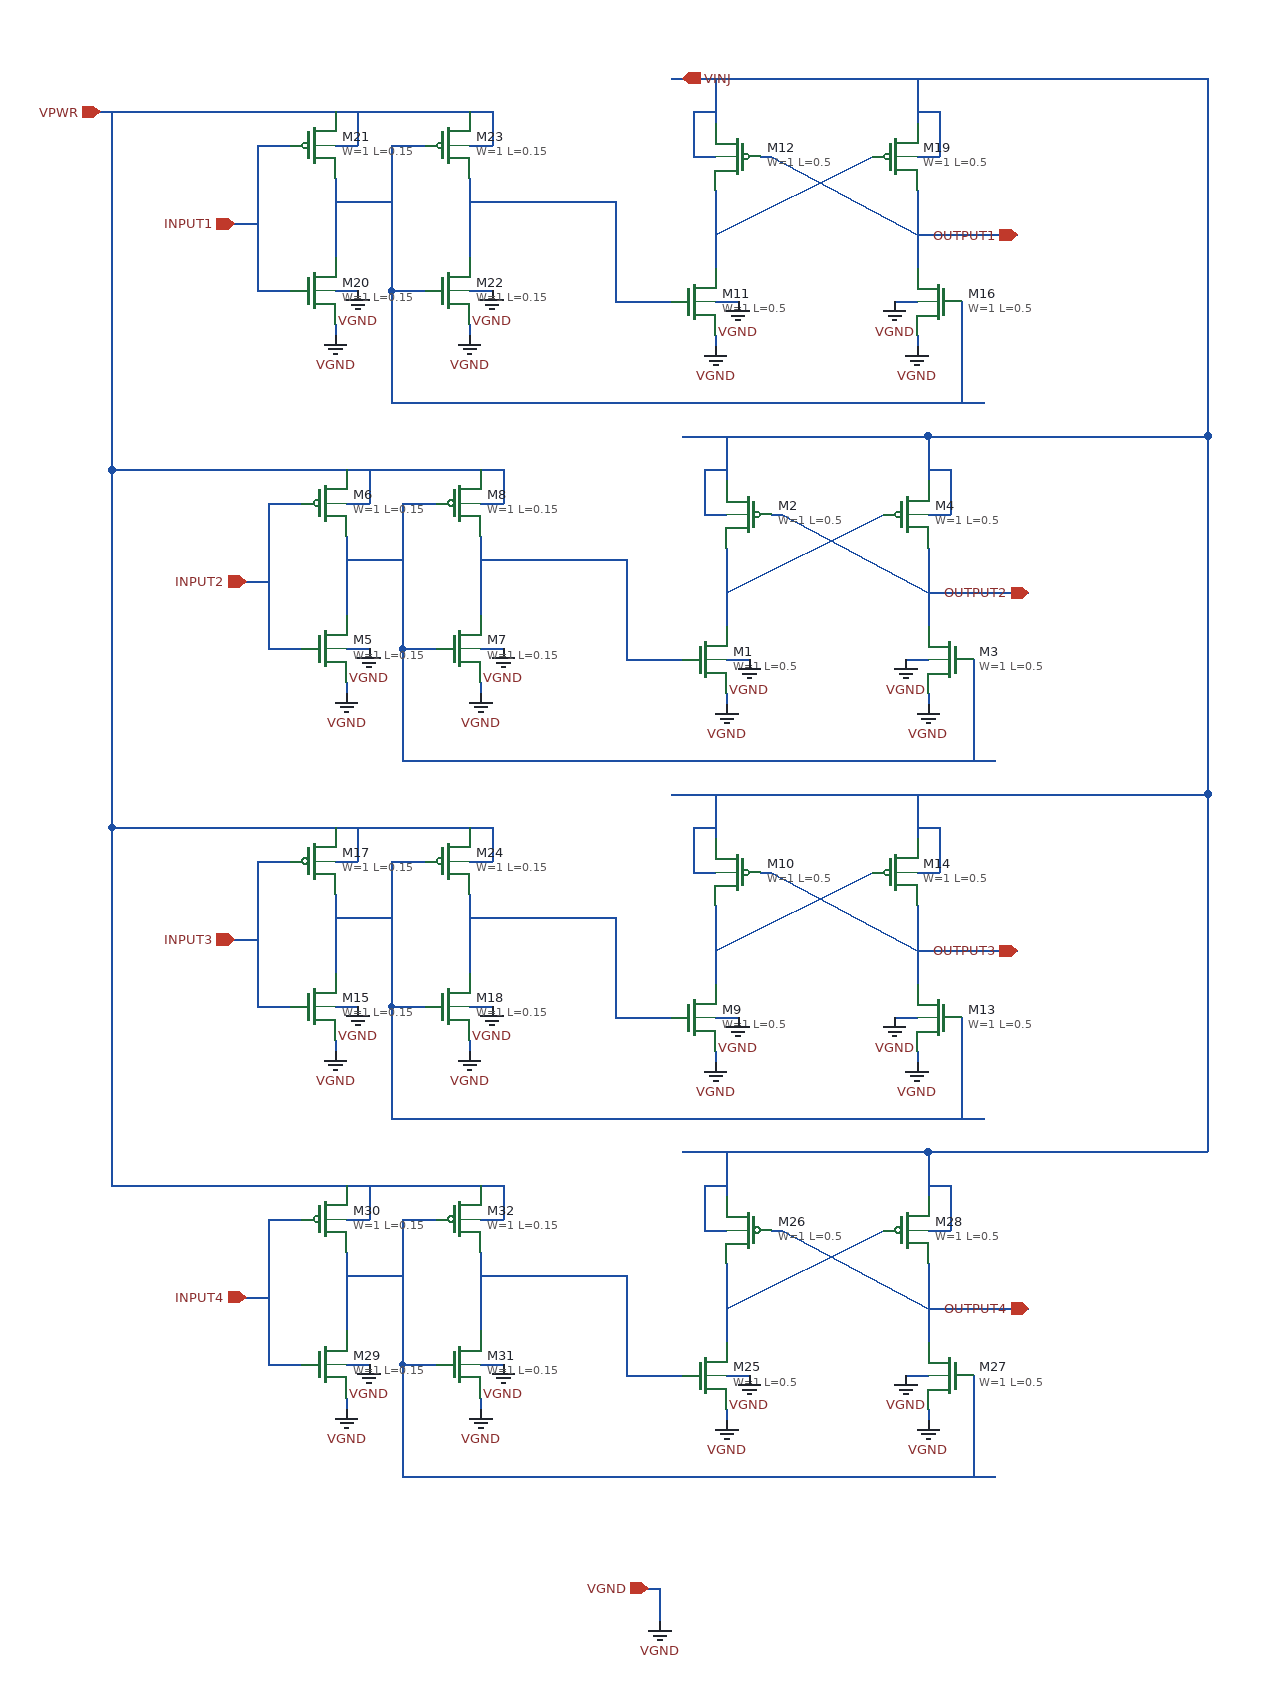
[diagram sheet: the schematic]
v {xschem version=2.9.9 file_version=1.2 }
G {}
K {}
V {}
S {}
E {}
N 2380 -1040 2380 -990 { lab=#net1}
N 2090 -1040 2120 -1040 { lab=#net2}
N 2320 -1040 2340 -1040 { lab=VGND}
N 2160 -1010 2160 -1000 { lab=VGND}
N 2160 -1040 2180 -1040 { lab=VGND}
N 1820 -1150 1820 -1080 { lab=#net1}
N 1750 -1050 1780 -1050 { lab=INPUT1}
N 1750 -1180 1780 -1180 { lab=INPUT1}
N 1820 -1180 1840 -1180 { lab=VPWR}
N 1840 -1210 1840 -1180 { lab=VPWR}
N 1820 -1210 1840 -1210 { lab=VPWR}
N 1650 -1210 1820 -1210 { lab=VPWR}
N 1820 -1020 1820 -1010 { lab=VGND}
N 1820 -1050 1840 -1050 { lab=VGND}
N 1820 -1130 1870 -1130 { lab=#net1}
N 1750 -1180 1750 -1050 { lab=INPUT1}
N 1730 -1110 1750 -1110 { lab=INPUT1}
N 1940 -1150 1940 -1080 { lab=#net2}
N 1870 -1050 1900 -1050 { lab=#net1}
N 1870 -1180 1900 -1180 { lab=#net1}
N 1940 -1180 1960 -1180 { lab=VPWR}
N 1960 -1210 1960 -1180 { lab=VPWR}
N 1940 -1210 1960 -1210 { lab=VPWR}
N 1940 -1020 1940 -1010 { lab=VGND}
N 1940 -1050 1960 -1050 { lab=VGND}
N 1940 -1130 1990 -1130 { lab=#net2}
N 1870 -1180 1870 -1050 { lab=#net1}
N 1830 -1210 1940 -1210 { lab=VPWR}
N 1870 -1050 1870 -950 { lab=#net1}
N 1870 -950 2000 -950 { lab=#net1}
N 2340 -1010 2340 -1000 { lab=VGND}
N 2120 -1240 2340 -1240 { lab=VINJ}
N 2160 -1240 2160 -1200 { lab=VINJ}
N 2340 -1240 2340 -1200 { lab=VINJ}
N 2140 -1210 2140 -1170 { lab=VINJ}
N 2140 -1170 2160 -1170 { lab=VINJ}
N 2340 -1170 2360 -1170 { lab=VINJ}
N 2360 -1210 2360 -1170 { lab=VINJ}
N 2340 -1210 2360 -1210 { lab=VINJ}
N 2160 -1140 2160 -1070 { lab=#net3}
N 2340 -1140 2340 -1070 { lab=OUTPUT1}
N 2210 -1170 2340 -1100 { lab=OUTPUT1}
N 2160 -1100 2300 -1170 { lab=#net3}
N 2340 -1100 2430 -1100 { lab=OUTPUT1}
N 2000 -950 2400 -950 { lab=#net1}
N 1990 -1130 2070 -1130 { lab=#net2}
N 2070 -1130 2070 -1040 { lab=#net2}
N 2070 -1040 2090 -1040 { lab=#net2}
N 2330 -1240 2600 -1240 { lab=VINJ}
N 1610 -1210 1650 -1210 { lab=VPWR}
N 2390 -720 2390 -670 { lab=#net4}
N 2100 -720 2130 -720 { lab=#net5}
N 2330 -720 2350 -720 { lab=VGND}
N 2170 -690 2170 -680 { lab=VGND}
N 2170 -720 2190 -720 { lab=VGND}
N 1830 -830 1830 -760 { lab=#net4}
N 1760 -730 1790 -730 { lab=INPUT2}
N 1760 -860 1790 -860 { lab=INPUT2}
N 1830 -860 1850 -860 { lab=VPWR}
N 1850 -890 1850 -860 { lab=VPWR}
N 1830 -890 1850 -890 { lab=VPWR}
N 1660 -890 1830 -890 { lab=VPWR}
N 1830 -700 1830 -690 { lab=VGND}
N 1830 -730 1850 -730 { lab=VGND}
N 1830 -810 1880 -810 { lab=#net4}
N 1760 -860 1760 -730 { lab=INPUT2}
N 1740 -790 1760 -790 { lab=INPUT2}
N 1950 -830 1950 -760 { lab=#net5}
N 1880 -730 1910 -730 { lab=#net4}
N 1880 -860 1910 -860 { lab=#net4}
N 1950 -860 1970 -860 { lab=VPWR}
N 1970 -890 1970 -860 { lab=VPWR}
N 1950 -890 1970 -890 { lab=VPWR}
N 1950 -700 1950 -690 { lab=VGND}
N 1950 -730 1970 -730 { lab=VGND}
N 1950 -810 2000 -810 { lab=#net5}
N 1880 -860 1880 -730 { lab=#net4}
N 1840 -890 1950 -890 { lab=VPWR}
N 1880 -730 1880 -630 { lab=#net4}
N 1880 -630 2010 -630 { lab=#net4}
N 2350 -690 2350 -680 { lab=VGND}
N 2130 -920 2350 -920 { lab=VINJ}
N 2170 -920 2170 -880 { lab=VINJ}
N 2350 -920 2350 -880 { lab=VINJ}
N 2150 -890 2170 -890 { lab=VINJ}
N 2150 -890 2150 -850 { lab=VINJ}
N 2150 -850 2170 -850 { lab=VINJ}
N 2350 -850 2370 -850 { lab=VINJ}
N 2370 -890 2370 -850 { lab=VINJ}
N 2350 -890 2370 -890 { lab=VINJ}
N 2170 -820 2170 -750 { lab=#net6}
N 2350 -820 2350 -750 { lab=OUTPUT2}
N 2220 -850 2350 -780 { lab=OUTPUT2}
N 2170 -780 2310 -850 { lab=#net6}
N 2350 -780 2440 -780 { lab=OUTPUT2}
N 2010 -630 2410 -630 { lab=#net4}
N 2000 -810 2080 -810 { lab=#net5}
N 2080 -810 2080 -720 { lab=#net5}
N 2080 -720 2100 -720 { lab=#net5}
N 1620 -890 1660 -890 { lab=VPWR}
N 1620 -1210 1620 -890 { lab=VPWR}
N 1620 -890 1620 -620 { lab=VPWR}
N 2600 -1240 2600 -920 { lab=VINJ}
N 2600 -920 2600 -620 { lab=VINJ}
N 2350 -920 2600 -920 { lab=VINJ}
N 2380 -400 2380 -350 { lab=#net7}
N 2090 -400 2120 -400 { lab=#net8}
N 2320 -400 2340 -400 { lab=VGND}
N 2160 -370 2160 -360 { lab=VGND}
N 2160 -400 2180 -400 { lab=VGND}
N 1820 -510 1820 -440 { lab=#net7}
N 1750 -410 1780 -410 { lab=INPUT3}
N 1750 -540 1780 -540 { lab=INPUT3}
N 1820 -540 1840 -540 { lab=VPWR}
N 1840 -570 1840 -540 { lab=VPWR}
N 1820 -570 1840 -570 { lab=VPWR}
N 1650 -570 1820 -570 { lab=VPWR}
N 1820 -380 1820 -370 { lab=VGND}
N 1820 -410 1840 -410 { lab=VGND}
N 1820 -490 1870 -490 { lab=#net7}
N 1750 -540 1750 -410 { lab=INPUT3}
N 1730 -470 1750 -470 { lab=INPUT3}
N 1940 -510 1940 -440 { lab=#net8}
N 1870 -410 1900 -410 { lab=#net7}
N 1870 -540 1900 -540 { lab=#net7}
N 1940 -540 1960 -540 { lab=VPWR}
N 1960 -570 1960 -540 { lab=VPWR}
N 1940 -570 1960 -570 { lab=VPWR}
N 1940 -380 1940 -370 { lab=VGND}
N 1940 -410 1960 -410 { lab=VGND}
N 1940 -490 1990 -490 { lab=#net8}
N 1870 -540 1870 -410 { lab=#net7}
N 1830 -570 1940 -570 { lab=VPWR}
N 1870 -410 1870 -310 { lab=#net7}
N 1870 -310 2000 -310 { lab=#net7}
N 2340 -370 2340 -360 { lab=VGND}
N 2120 -600 2340 -600 { lab=VINJ}
N 2160 -600 2160 -560 { lab=VINJ}
N 2340 -600 2340 -560 { lab=VINJ}
N 2140 -570 2160 -570 { lab=VINJ}
N 2140 -570 2140 -530 { lab=VINJ}
N 2140 -530 2160 -530 { lab=VINJ}
N 2340 -530 2360 -530 { lab=VINJ}
N 2360 -570 2360 -530 { lab=VINJ}
N 2340 -570 2360 -570 { lab=VINJ}
N 2160 -500 2160 -430 { lab=#net9}
N 2340 -500 2340 -430 { lab=OUTPUT3}
N 2210 -530 2340 -460 { lab=OUTPUT3}
N 2160 -460 2300 -530 { lab=#net9}
N 2340 -460 2430 -460 { lab=OUTPUT3}
N 2000 -310 2400 -310 { lab=#net7}
N 1990 -490 2070 -490 { lab=#net8}
N 2070 -490 2070 -400 { lab=#net8}
N 2070 -400 2090 -400 { lab=#net8}
N 2330 -600 2600 -600 { lab=VINJ}
N 2390 -80 2390 -30 { lab=#net10}
N 2100 -80 2130 -80 { lab=#net11}
N 2330 -80 2350 -80 { lab=VGND}
N 2170 -50 2170 -40 { lab=VGND}
N 2170 -80 2190 -80 { lab=VGND}
N 1830 -190 1830 -120 { lab=#net10}
N 1760 -90 1790 -90 { lab=INPUT4}
N 1760 -220 1790 -220 { lab=INPUT4}
N 1830 -220 1850 -220 { lab=VPWR}
N 1850 -250 1850 -220 { lab=VPWR}
N 1830 -250 1850 -250 { lab=VPWR}
N 1660 -250 1830 -250 { lab=VPWR}
N 1830 -60 1830 -50 { lab=VGND}
N 1830 -90 1850 -90 { lab=VGND}
N 1830 -170 1880 -170 { lab=#net10}
N 1760 -220 1760 -90 { lab=INPUT4}
N 1740 -150 1760 -150 { lab=INPUT4}
N 1950 -190 1950 -120 { lab=#net11}
N 1880 -90 1910 -90 { lab=#net10}
N 1880 -220 1910 -220 { lab=#net10}
N 1950 -220 1970 -220 { lab=VPWR}
N 1970 -250 1970 -220 { lab=VPWR}
N 1950 -250 1970 -250 { lab=VPWR}
N 1950 -60 1950 -50 { lab=VGND}
N 1950 -90 1970 -90 { lab=VGND}
N 1950 -170 2000 -170 { lab=#net11}
N 1880 -220 1880 -90 { lab=#net10}
N 1840 -250 1950 -250 { lab=VPWR}
N 1880 -90 1880 10 { lab=#net10}
N 1880 10 2010 10 { lab=#net10}
N 2350 -50 2350 -40 { lab=VGND}
N 2130 -280 2350 -280 { lab=VINJ}
N 2170 -280 2170 -240 { lab=VINJ}
N 2350 -280 2350 -240 { lab=VINJ}
N 2150 -250 2170 -250 { lab=VINJ}
N 2150 -250 2150 -210 { lab=VINJ}
N 2150 -210 2170 -210 { lab=VINJ}
N 2350 -210 2370 -210 { lab=VINJ}
N 2370 -250 2370 -210 { lab=VINJ}
N 2350 -250 2370 -250 { lab=VINJ}
N 2170 -180 2170 -110 { lab=#net12}
N 2350 -180 2350 -110 { lab=OUTPUT4}
N 2220 -210 2350 -140 { lab=OUTPUT4}
N 2170 -140 2310 -210 { lab=#net12}
N 2350 -140 2440 -140 { lab=OUTPUT4}
N 2010 10 2410 10 { lab=#net10}
N 2000 -170 2080 -170 { lab=#net11}
N 2080 -170 2080 -80 { lab=#net11}
N 2080 -80 2100 -80 { lab=#net11}
N 1620 -250 1660 -250 { lab=VPWR}
N 1620 -570 1620 -250 { lab=VPWR}
N 2600 -600 2600 -280 { lab=VINJ}
N 2350 -280 2600 -280 { lab=VINJ}
N 2600 -630 2600 -610 { lab=VINJ}
N 2600 -620 2600 -600 { lab=VINJ}
N 1620 -620 1620 -570 { lab=VPWR}
N 1620 -570 1650 -570 { lab=VPWR}
N 2200 -1170 2210 -1170 { lab=OUTPUT1}
N 2210 -850 2220 -850 { lab=OUTPUT2}
N 2200 -530 2210 -530 { lab=OUTPUT3}
N 2210 -210 2220 -210 { lab=OUTPUT4}
N 2140 -1210 2160 -1210 { lab=VINJ}
N 2390 -30 2390 10 { lab=#net10}
N 2380 -350 2380 -310 { lab=#net7}
N 2390 -670 2390 -630 { lab=#net4}
N 2380 -990 2380 -950 { lab=#net1}
N 2090 110 2110 110 {}
N 2110 110 2110 140 {}
C {sky130_fd_pr/nfet_g5v0d10v5.sym} 2140 -1040 0 0 {name=M11
L=0.5
W=1
nf=1
mult=1
ad="'int((nf+1)/2) * W/nf * 0.29'" 
pd="'2*int((nf+1)/2) * (W/nf + 0.29)'"
as="'int((nf+2)/2) * W/nf * 0.29'" 
ps="'2*int((nf+2)/2) * (W/nf + 0.29)'"
nrd="'0.29 / W'" nrs="'0.29 / W'"
sa=0 sb=0 sd=0
model=nfet_g5v0d10v5
spiceprefix=X
}
C {sky130_fd_pr/pfet_g5v0d10v5.sym} 2180 -1170 0 1 {name=M12
L=0.5
W=1
nf=1
mult=1
ad="'int((nf+1)/2) * W/nf * 0.29'" 
pd="'2*int((nf+1)/2) * (W/nf + 0.29)'"
as="'int((nf+2)/2) * W/nf * 0.29'" 
ps="'2*int((nf+2)/2) * (W/nf + 0.29)'"
nrd="'0.29 / W'" nrs="'0.29 / W'"
sa=0 sb=0 sd=0
model=pfet_g5v0d10v5
spiceprefix=X
}
C {sky130_fd_pr/nfet_g5v0d10v5.sym} 2360 -1040 0 1 {name=M16
L=0.5
W=1
nf=1
mult=1
ad="'int((nf+1)/2) * W/nf * 0.29'" 
pd="'2*int((nf+1)/2) * (W/nf + 0.29)'"
as="'int((nf+2)/2) * W/nf * 0.29'" 
ps="'2*int((nf+2)/2) * (W/nf + 0.29)'"
nrd="'0.29 / W'" nrs="'0.29 / W'"
sa=0 sb=0 sd=0
model=nfet_g5v0d10v5
spiceprefix=X
}
C {devices/gnd.sym} 2320 -1040 0 0 {name=l10 lab=VGND}
C {devices/gnd.sym} 2180 -1040 0 0 {name=l11 lab=VGND}
C {devices/gnd.sym} 2160 -1000 0 0 {name=l12 lab=VGND}
C {devices/iopin.sym} 2430 -1100 0 0 {name=OUTPUT1 lab=OUTPUT1}
C {devices/ipin.sym} 1730 -1110 0 0 {name=INPUT1 lab=INPUT1}
C {sky130_fd_pr/pfet_g5v0d10v5.sym} 2320 -1170 0 0 {name=M19
L=0.5
W=1
nf=1
mult=1
ad="'int((nf+1)/2) * W/nf * 0.29'" 
pd="'2*int((nf+1)/2) * (W/nf + 0.29)'"
as="'int((nf+2)/2) * W/nf * 0.29'" 
ps="'2*int((nf+2)/2) * (W/nf + 0.29)'"
nrd="'0.29 / W'" nrs="'0.29 / W'"
sa=0 sb=0 sd=0
model=pfet_g5v0d10v5
spiceprefix=X
}
C {devices/gnd.sym} 1840 -1050 0 0 {name=l13 lab=VGND}
C {devices/gnd.sym} 1820 -1010 0 0 {name=l14 lab=VGND}
C {sky130_fd_pr/nfet_01v8.sym} 1800 -1050 0 0 {name=M20
L=0.15
W=1
nf=1 
mult=1
ad="'int((nf+1)/2) * W/nf * 0.29'" 
pd="'2*int((nf+1)/2) * (W/nf + 0.29)'"
as="'int((nf+2)/2) * W/nf * 0.29'" 
ps="'2*int((nf+2)/2) * (W/nf + 0.29)'"
nrd="'0.29 / W'" nrs="'0.29 / W'"
sa=0 sb=0 sd=0
model=nfet_01v8
spiceprefix=X
}
C {sky130_fd_pr/pfet_01v8.sym} 1800 -1180 0 0 {name=M21
L=0.15
W=1
nf=1
mult=1
ad="'int((nf+1)/2) * W/nf * 0.29'" 
pd="'2*int((nf+1)/2) * (W/nf + 0.29)'"
as="'int((nf+2)/2) * W/nf * 0.29'" 
ps="'2*int((nf+2)/2) * (W/nf + 0.29)'"
nrd="'0.29 / W'" nrs="'0.29 / W'"
sa=0 sb=0 sd=0
model=pfet_01v8
spiceprefix=X
}
C {devices/ipin.sym} 1610 -1210 0 0 {name=VPWR lab=VPWR}
C {devices/gnd.sym} 1960 -1050 0 0 {name=l15 lab=VGND}
C {devices/gnd.sym} 1940 -1010 0 0 {name=l16 lab=VGND}
C {sky130_fd_pr/nfet_01v8.sym} 1920 -1050 0 0 {name=M22
L=0.15
W=1
nf=1 
mult=1
ad="'int((nf+1)/2) * W/nf * 0.29'" 
pd="'2*int((nf+1)/2) * (W/nf + 0.29)'"
as="'int((nf+2)/2) * W/nf * 0.29'" 
ps="'2*int((nf+2)/2) * (W/nf + 0.29)'"
nrd="'0.29 / W'" nrs="'0.29 / W'"
sa=0 sb=0 sd=0
model=nfet_01v8
spiceprefix=X
}
C {sky130_fd_pr/pfet_01v8.sym} 1920 -1180 0 0 {name=M23
L=0.15
W=1
nf=1
mult=1
ad="'int((nf+1)/2) * W/nf * 0.29'" 
pd="'2*int((nf+1)/2) * (W/nf + 0.29)'"
as="'int((nf+2)/2) * W/nf * 0.29'" 
ps="'2*int((nf+2)/2) * (W/nf + 0.29)'"
nrd="'0.29 / W'" nrs="'0.29 / W'"
sa=0 sb=0 sd=0
model=pfet_01v8
spiceprefix=X
}
C {devices/gnd.sym} 2340 -1000 0 0 {name=l17 lab=VGND}
C {sky130_fd_pr/nfet_g5v0d10v5.sym} 2150 -720 0 0 {name=M1
L=0.5
W=1
nf=1
mult=1
ad="'int((nf+1)/2) * W/nf * 0.29'" 
pd="'2*int((nf+1)/2) * (W/nf + 0.29)'"
as="'int((nf+2)/2) * W/nf * 0.29'" 
ps="'2*int((nf+2)/2) * (W/nf + 0.29)'"
nrd="'0.29 / W'" nrs="'0.29 / W'"
sa=0 sb=0 sd=0
model=nfet_g5v0d10v5
spiceprefix=X
}
C {sky130_fd_pr/pfet_g5v0d10v5.sym} 2190 -850 0 1 {name=M2
L=0.5
W=1
nf=1
mult=1
ad="'int((nf+1)/2) * W/nf * 0.29'" 
pd="'2*int((nf+1)/2) * (W/nf + 0.29)'"
as="'int((nf+2)/2) * W/nf * 0.29'" 
ps="'2*int((nf+2)/2) * (W/nf + 0.29)'"
nrd="'0.29 / W'" nrs="'0.29 / W'"
sa=0 sb=0 sd=0
model=pfet_g5v0d10v5
spiceprefix=X
}
C {sky130_fd_pr/nfet_g5v0d10v5.sym} 2370 -720 0 1 {name=M3
L=0.5
W=1
nf=1
mult=1
ad="'int((nf+1)/2) * W/nf * 0.29'" 
pd="'2*int((nf+1)/2) * (W/nf + 0.29)'"
as="'int((nf+2)/2) * W/nf * 0.29'" 
ps="'2*int((nf+2)/2) * (W/nf + 0.29)'"
nrd="'0.29 / W'" nrs="'0.29 / W'"
sa=0 sb=0 sd=0
model=nfet_g5v0d10v5
spiceprefix=X
}
C {devices/gnd.sym} 2330 -720 0 0 {name=l1 lab=VGND}
C {devices/gnd.sym} 2190 -720 0 0 {name=l2 lab=VGND}
C {devices/gnd.sym} 2170 -680 0 0 {name=l3 lab=VGND}
C {devices/iopin.sym} 2440 -780 0 0 {name=OUTPUT2 lab=OUTPUT2}
C {devices/ipin.sym} 1740 -790 0 0 {name=INPUT2 lab=INPUT2}
C {sky130_fd_pr/pfet_g5v0d10v5.sym} 2330 -850 0 0 {name=M4
L=0.5
W=1
nf=1
mult=1
ad="'int((nf+1)/2) * W/nf * 0.29'" 
pd="'2*int((nf+1)/2) * (W/nf + 0.29)'"
as="'int((nf+2)/2) * W/nf * 0.29'" 
ps="'2*int((nf+2)/2) * (W/nf + 0.29)'"
nrd="'0.29 / W'" nrs="'0.29 / W'"
sa=0 sb=0 sd=0
model=pfet_g5v0d10v5
spiceprefix=X
}
C {devices/gnd.sym} 1850 -730 0 0 {name=l4 lab=VGND}
C {devices/gnd.sym} 1830 -690 0 0 {name=l5 lab=VGND}
C {sky130_fd_pr/nfet_01v8.sym} 1810 -730 0 0 {name=M5
L=0.15
W=1
nf=1 
mult=1
ad="'int((nf+1)/2) * W/nf * 0.29'" 
pd="'2*int((nf+1)/2) * (W/nf + 0.29)'"
as="'int((nf+2)/2) * W/nf * 0.29'" 
ps="'2*int((nf+2)/2) * (W/nf + 0.29)'"
nrd="'0.29 / W'" nrs="'0.29 / W'"
sa=0 sb=0 sd=0
model=nfet_01v8
spiceprefix=X
}
C {sky130_fd_pr/pfet_01v8.sym} 1810 -860 0 0 {name=M6
L=0.15
W=1
nf=1
mult=1
ad="'int((nf+1)/2) * W/nf * 0.29'" 
pd="'2*int((nf+1)/2) * (W/nf + 0.29)'"
as="'int((nf+2)/2) * W/nf * 0.29'" 
ps="'2*int((nf+2)/2) * (W/nf + 0.29)'"
nrd="'0.29 / W'" nrs="'0.29 / W'"
sa=0 sb=0 sd=0
model=pfet_01v8
spiceprefix=X
}
C {devices/gnd.sym} 1970 -730 0 0 {name=l6 lab=VGND}
C {devices/gnd.sym} 1950 -690 0 0 {name=l7 lab=VGND}
C {sky130_fd_pr/nfet_01v8.sym} 1930 -730 0 0 {name=M7
L=0.15
W=1
nf=1 
mult=1
ad="'int((nf+1)/2) * W/nf * 0.29'" 
pd="'2*int((nf+1)/2) * (W/nf + 0.29)'"
as="'int((nf+2)/2) * W/nf * 0.29'" 
ps="'2*int((nf+2)/2) * (W/nf + 0.29)'"
nrd="'0.29 / W'" nrs="'0.29 / W'"
sa=0 sb=0 sd=0
model=nfet_01v8
spiceprefix=X
}
C {sky130_fd_pr/pfet_01v8.sym} 1930 -860 0 0 {name=M8
L=0.15
W=1
nf=1
mult=1
ad="'int((nf+1)/2) * W/nf * 0.29'" 
pd="'2*int((nf+1)/2) * (W/nf + 0.29)'"
as="'int((nf+2)/2) * W/nf * 0.29'" 
ps="'2*int((nf+2)/2) * (W/nf + 0.29)'"
nrd="'0.29 / W'" nrs="'0.29 / W'"
sa=0 sb=0 sd=0
model=pfet_01v8
spiceprefix=X
}
C {devices/gnd.sym} 2350 -680 0 0 {name=l8 lab=VGND}
C {sky130_fd_pr/nfet_g5v0d10v5.sym} 2140 -400 0 0 {name=M9
L=0.5
W=1
nf=1
mult=1
ad="'int((nf+1)/2) * W/nf * 0.29'" 
pd="'2*int((nf+1)/2) * (W/nf + 0.29)'"
as="'int((nf+2)/2) * W/nf * 0.29'" 
ps="'2*int((nf+2)/2) * (W/nf + 0.29)'"
nrd="'0.29 / W'" nrs="'0.29 / W'"
sa=0 sb=0 sd=0
model=nfet_g5v0d10v5
spiceprefix=X
}
C {sky130_fd_pr/pfet_g5v0d10v5.sym} 2180 -530 0 1 {name=M10
L=0.5
W=1
nf=1
mult=1
ad="'int((nf+1)/2) * W/nf * 0.29'" 
pd="'2*int((nf+1)/2) * (W/nf + 0.29)'"
as="'int((nf+2)/2) * W/nf * 0.29'" 
ps="'2*int((nf+2)/2) * (W/nf + 0.29)'"
nrd="'0.29 / W'" nrs="'0.29 / W'"
sa=0 sb=0 sd=0
model=pfet_g5v0d10v5
spiceprefix=X
}
C {sky130_fd_pr/nfet_g5v0d10v5.sym} 2360 -400 0 1 {name=M13
L=0.5
W=1
nf=1
mult=1
ad="'int((nf+1)/2) * W/nf * 0.29'" 
pd="'2*int((nf+1)/2) * (W/nf + 0.29)'"
as="'int((nf+2)/2) * W/nf * 0.29'" 
ps="'2*int((nf+2)/2) * (W/nf + 0.29)'"
nrd="'0.29 / W'" nrs="'0.29 / W'"
sa=0 sb=0 sd=0
model=nfet_g5v0d10v5
spiceprefix=X
}
C {devices/gnd.sym} 2320 -400 0 0 {name=l9 lab=VGND}
C {devices/gnd.sym} 2180 -400 0 0 {name=l18 lab=VGND}
C {devices/gnd.sym} 2160 -360 0 0 {name=l19 lab=VGND}
C {devices/iopin.sym} 2430 -460 0 0 {name=OUTPUT3 lab=OUTPUT3}
C {devices/ipin.sym} 1730 -470 0 0 {name=INPUT3 lab=INPUT3}
C {sky130_fd_pr/pfet_g5v0d10v5.sym} 2320 -530 0 0 {name=M14
L=0.5
W=1
nf=1
mult=1
ad="'int((nf+1)/2) * W/nf * 0.29'" 
pd="'2*int((nf+1)/2) * (W/nf + 0.29)'"
as="'int((nf+2)/2) * W/nf * 0.29'" 
ps="'2*int((nf+2)/2) * (W/nf + 0.29)'"
nrd="'0.29 / W'" nrs="'0.29 / W'"
sa=0 sb=0 sd=0
model=pfet_g5v0d10v5
spiceprefix=X
}
C {devices/gnd.sym} 1840 -410 0 0 {name=l20 lab=VGND}
C {devices/gnd.sym} 1820 -370 0 0 {name=l21 lab=VGND}
C {sky130_fd_pr/nfet_01v8.sym} 1800 -410 0 0 {name=M15
L=0.15
W=1
nf=1 
mult=1
ad="'int((nf+1)/2) * W/nf * 0.29'" 
pd="'2*int((nf+1)/2) * (W/nf + 0.29)'"
as="'int((nf+2)/2) * W/nf * 0.29'" 
ps="'2*int((nf+2)/2) * (W/nf + 0.29)'"
nrd="'0.29 / W'" nrs="'0.29 / W'"
sa=0 sb=0 sd=0
model=nfet_01v8
spiceprefix=X
}
C {sky130_fd_pr/pfet_01v8.sym} 1800 -540 0 0 {name=M17
L=0.15
W=1
nf=1
mult=1
ad="'int((nf+1)/2) * W/nf * 0.29'" 
pd="'2*int((nf+1)/2) * (W/nf + 0.29)'"
as="'int((nf+2)/2) * W/nf * 0.29'" 
ps="'2*int((nf+2)/2) * (W/nf + 0.29)'"
nrd="'0.29 / W'" nrs="'0.29 / W'"
sa=0 sb=0 sd=0
model=pfet_01v8
spiceprefix=X
}
C {devices/gnd.sym} 1960 -410 0 0 {name=l22 lab=VGND}
C {devices/gnd.sym} 1940 -370 0 0 {name=l23 lab=VGND}
C {sky130_fd_pr/nfet_01v8.sym} 1920 -410 0 0 {name=M18
L=0.15
W=1
nf=1 
mult=1
ad="'int((nf+1)/2) * W/nf * 0.29'" 
pd="'2*int((nf+1)/2) * (W/nf + 0.29)'"
as="'int((nf+2)/2) * W/nf * 0.29'" 
ps="'2*int((nf+2)/2) * (W/nf + 0.29)'"
nrd="'0.29 / W'" nrs="'0.29 / W'"
sa=0 sb=0 sd=0
model=nfet_01v8
spiceprefix=X
}
C {sky130_fd_pr/pfet_01v8.sym} 1920 -540 0 0 {name=M24
L=0.15
W=1
nf=1
mult=1
ad="'int((nf+1)/2) * W/nf * 0.29'" 
pd="'2*int((nf+1)/2) * (W/nf + 0.29)'"
as="'int((nf+2)/2) * W/nf * 0.29'" 
ps="'2*int((nf+2)/2) * (W/nf + 0.29)'"
nrd="'0.29 / W'" nrs="'0.29 / W'"
sa=0 sb=0 sd=0
model=pfet_01v8
spiceprefix=X
}
C {devices/gnd.sym} 2340 -360 0 0 {name=l24 lab=VGND}
C {sky130_fd_pr/nfet_g5v0d10v5.sym} 2150 -80 0 0 {name=M25
L=0.5
W=1
nf=1
mult=1
ad="'int((nf+1)/2) * W/nf * 0.29'" 
pd="'2*int((nf+1)/2) * (W/nf + 0.29)'"
as="'int((nf+2)/2) * W/nf * 0.29'" 
ps="'2*int((nf+2)/2) * (W/nf + 0.29)'"
nrd="'0.29 / W'" nrs="'0.29 / W'"
sa=0 sb=0 sd=0
model=nfet_g5v0d10v5
spiceprefix=X
}
C {sky130_fd_pr/pfet_g5v0d10v5.sym} 2190 -210 0 1 {name=M26
L=0.5
W=1
nf=1
mult=1
ad="'int((nf+1)/2) * W/nf * 0.29'" 
pd="'2*int((nf+1)/2) * (W/nf + 0.29)'"
as="'int((nf+2)/2) * W/nf * 0.29'" 
ps="'2*int((nf+2)/2) * (W/nf + 0.29)'"
nrd="'0.29 / W'" nrs="'0.29 / W'"
sa=0 sb=0 sd=0
model=pfet_g5v0d10v5
spiceprefix=X
}
C {sky130_fd_pr/nfet_g5v0d10v5.sym} 2370 -80 0 1 {name=M27
L=0.5
W=1
nf=1
mult=1
ad="'int((nf+1)/2) * W/nf * 0.29'" 
pd="'2*int((nf+1)/2) * (W/nf + 0.29)'"
as="'int((nf+2)/2) * W/nf * 0.29'" 
ps="'2*int((nf+2)/2) * (W/nf + 0.29)'"
nrd="'0.29 / W'" nrs="'0.29 / W'"
sa=0 sb=0 sd=0
model=nfet_g5v0d10v5
spiceprefix=X
}
C {devices/gnd.sym} 2330 -80 0 0 {name=l25 lab=VGND}
C {devices/gnd.sym} 2190 -80 0 0 {name=l26 lab=VGND}
C {devices/gnd.sym} 2170 -40 0 0 {name=l27 lab=VGND}
C {devices/iopin.sym} 2440 -140 0 0 {name=OUTPUT4 lab=OUTPUT4}
C {devices/ipin.sym} 1740 -150 0 0 {name=INPUT4 lab=INPUT4}
C {sky130_fd_pr/pfet_g5v0d10v5.sym} 2330 -210 0 0 {name=M28
L=0.5
W=1
nf=1
mult=1
ad="'int((nf+1)/2) * W/nf * 0.29'" 
pd="'2*int((nf+1)/2) * (W/nf + 0.29)'"
as="'int((nf+2)/2) * W/nf * 0.29'" 
ps="'2*int((nf+2)/2) * (W/nf + 0.29)'"
nrd="'0.29 / W'" nrs="'0.29 / W'"
sa=0 sb=0 sd=0
model=pfet_g5v0d10v5
spiceprefix=X
}
C {devices/gnd.sym} 1850 -90 0 0 {name=l28 lab=VGND}
C {devices/gnd.sym} 1830 -50 0 0 {name=l29 lab=VGND}
C {sky130_fd_pr/nfet_01v8.sym} 1810 -90 0 0 {name=M29
L=0.15
W=1
nf=1 
mult=1
ad="'int((nf+1)/2) * W/nf * 0.29'" 
pd="'2*int((nf+1)/2) * (W/nf + 0.29)'"
as="'int((nf+2)/2) * W/nf * 0.29'" 
ps="'2*int((nf+2)/2) * (W/nf + 0.29)'"
nrd="'0.29 / W'" nrs="'0.29 / W'"
sa=0 sb=0 sd=0
model=nfet_01v8
spiceprefix=X
}
C {sky130_fd_pr/pfet_01v8.sym} 1810 -220 0 0 {name=M30
L=0.15
W=1
nf=1
mult=1
ad="'int((nf+1)/2) * W/nf * 0.29'" 
pd="'2*int((nf+1)/2) * (W/nf + 0.29)'"
as="'int((nf+2)/2) * W/nf * 0.29'" 
ps="'2*int((nf+2)/2) * (W/nf + 0.29)'"
nrd="'0.29 / W'" nrs="'0.29 / W'"
sa=0 sb=0 sd=0
model=pfet_01v8
spiceprefix=X
}
C {devices/gnd.sym} 1970 -90 0 0 {name=l30 lab=VGND}
C {devices/gnd.sym} 1950 -50 0 0 {name=l31 lab=VGND}
C {sky130_fd_pr/nfet_01v8.sym} 1930 -90 0 0 {name=M31
L=0.15
W=1
nf=1 
mult=1
ad="'int((nf+1)/2) * W/nf * 0.29'" 
pd="'2*int((nf+1)/2) * (W/nf + 0.29)'"
as="'int((nf+2)/2) * W/nf * 0.29'" 
ps="'2*int((nf+2)/2) * (W/nf + 0.29)'"
nrd="'0.29 / W'" nrs="'0.29 / W'"
sa=0 sb=0 sd=0
model=nfet_01v8
spiceprefix=X
}
C {sky130_fd_pr/pfet_01v8.sym} 1930 -220 0 0 {name=M32
L=0.15
W=1
nf=1
mult=1
ad="'int((nf+1)/2) * W/nf * 0.29'" 
pd="'2*int((nf+1)/2) * (W/nf + 0.29)'"
as="'int((nf+2)/2) * W/nf * 0.29'" 
ps="'2*int((nf+2)/2) * (W/nf + 0.29)'"
nrd="'0.29 / W'" nrs="'0.29 / W'"
sa=0 sb=0 sd=0
model=pfet_01v8
spiceprefix=X
}
C {devices/gnd.sym} 2350 -40 0 0 {name=l32 lab=VGND}
C {devices/iopin.sym} 2130 -1240 0 1 {name=VINJ lab=VINJ}
C {devices/gnd.sym} 2110 140 0 0 {name=l33 lab=VGND}
C {devices/ipin.sym} 2100 110 0 0 {name=VGND lab=VGND}
